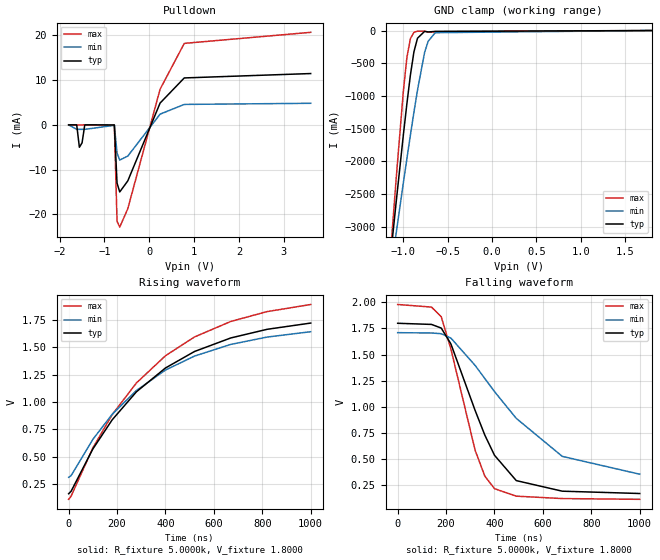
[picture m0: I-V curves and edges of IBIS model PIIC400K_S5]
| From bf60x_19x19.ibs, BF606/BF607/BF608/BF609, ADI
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[Model]  PIIC400K_S5
Model_type I/O_open_drain
Polarity   Non-Inverting
Enable   Active-Low
Vinl =   0.5400V
Vinh =   1.2600V
Vmeas =  0.9000V
Cref =   50.0000pF
Rref =   5.0000k
Vref =   1.8000V
C_comp   5.3246pF   5.6155pF   5.1879pF
[Temperature Range]   25.0000   0.1250k   -40.0000
[Voltage Range]   1.8000V   1.7100V   1.9800V
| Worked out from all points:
|   slope of the pulldown table from 0 to 0.27 V, typ, clamps not added: 50.4 ohm
|   rising waveform, R_fixture 5.0000k, V_fixture 1.8000: 20-80 % time 397ns typ, 397ns min, 398ns max; typ from 0.161 V to 1.72 V
|   falling waveform, R_fixture 5.0000k, V_fixture 1.8000: 20-80 % time 168ns typ, 306ns min, 119ns max; typ from 1.8 V to 0.168 V
[Pulldown]
|Voltage   I(typ)   I(min)   I(max)
-1.8V     0A         0A         0A
-1.62V    0A         -1mA       0A
-1.56V    -5mA       -1mA       0A
-1.5V     -4mA       -1mA       0A
-1.44V    0A         -1mA       0A
-780mV    -20uA      -100uA     -63uA
-720mV    -13.01mA   -6.3mA     -21.52mA
-660mV    -14.98mA   -7.86mA    -22.85mA
-480mV    -12.51mA   -6.972mA   -18.72mA
240mV     4.868mA    2.395mA    7.96mA
780mV     10.49mA    4.573mA    18.21mA
3.6V      11.47mA    4.825mA    20.68mA
[GND_clamp]
|Voltage   I(typ)   I(min)   I(max)
-1.8V     -12.65A    -10.37A    -16.09A
-1.12V    -3.145A    -3.485A    -2.97A
-1.08V    -2.62A     -3.098A    -2.26A
-1V       -1.604A    -2.336A    -936.9mA
-960mV    -1.124A    -1.964A    -416mA
-920mV    -680.1mA   -1.6A      -122.9mA
-880mV    -323.6mA   -1.247A    -27.4mA
-840mV    -117.5mA   -911.1mA   -9.271mA
-760mV    -12.74mA   -333.5mA   -9.089mA
-720mV    -21.78mA   -164.5mA   -26.29mA
-640mV    -13.84mA   -32.86mA   -16.42mA
1.8V      194.7pA    170.9uA    -341.8uA
[Ramp]
| variable   typ   min   max
dV/dt_r  0.9370/0.3980u   0.7991/0.3975u   1.0696/0.3987u
dV/dt_f  0.9790/0.1682u   0.8140/0.3064u   1.1205/0.1189u
R_load = 5.0000k
[Rising Waveform]
R_fixture= 5.0000k
V_fixture= 1.8000
V_fixture_min= 1.7100
V_fixture_max= 1.9800
|time   V(typ)   V(min)   V(max)
0s        161.3mV    312.2mV    110.3mV
10.1ns    183.6mV    327.1mV    138.9mV
100ns     570.9mV    658.8mV    580.4mV
180ns     838mV      888.6mV    885.3mV
280ns     1.094V     1.106V     1.175V
400ns     1.312V     1.293V     1.424V
520ns     1.463V     1.421V     1.596V
670ns     1.587V     1.528V     1.738V
820ns     1.666V     1.595V     1.828V
1us       1.723V     1.644V     1.893V
[Falling Waveform]
R_fixture= 5.0000k
V_fixture= 1.8000
V_fixture_min= 1.7100
V_fixture_max= 1.9800
|time   V(typ)   V(min)   V(max)
0s        1.8V       1.71V      1.98V
140ns     1.789V     1.707V     1.955V
180ns     1.754V     1.7V       1.863V
220ns     1.602V     1.658V     1.553V
320ns     964.5mV    1.396V     582.7mV
360ns     728.8mV    1.271V     335.7mV
400ns     535mV      1.145V     214.7mV
490ns     292mV      888.6mV    142.9mV
680ns     190.6mV    524.3mV    119.8mV
1us       168.3mV    353.3mV    112.5mV
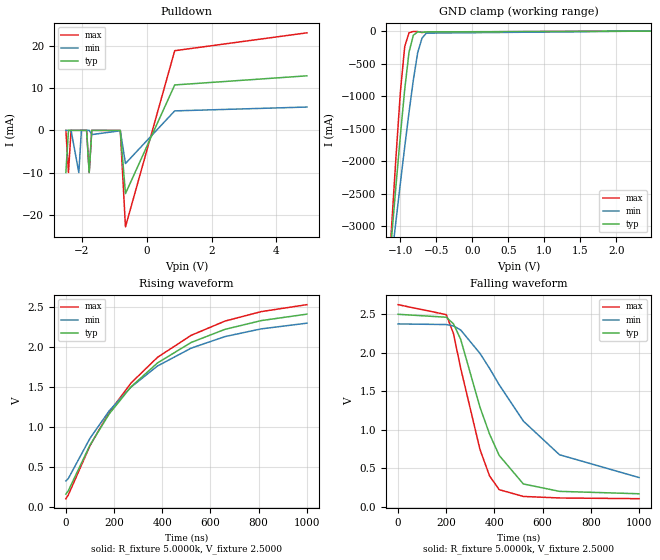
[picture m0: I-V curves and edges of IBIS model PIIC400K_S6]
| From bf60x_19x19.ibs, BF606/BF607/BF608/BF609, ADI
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[Model]  PIIC400K_S6
Model_type I/O_open_drain
Polarity   Non-Inverting
Enable   Active-Low
Vinl =   0.7500V
Vinh =   1.7500V
Vmeas =  1.2500V
Cref =   50.0000pF
Rref =   5.0000k
Vref =   2.5000V
C_comp   5.3246pF   5.6155pF   5.1879pF
[Temperature Range]   25.0000   0.1250k   -40.0000
[Voltage Range]   2.5000V   2.3750V   2.6250V
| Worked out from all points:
|   slope of the pulldown table from 0 to 0.375 V, typ, clamps not added: 53.9 ohm
|   rising waveform, R_fixture 5.0000k, V_fixture 2.5000: 20-80 % time 388ns typ, 387ns min, 388ns max; typ from 0.162 V to 2.4 V
|   falling waveform, R_fixture 5.0000k, V_fixture 2.5000: 20-80 % time 151ns typ, 283ns min, 114ns max; typ from 2.5 V to 0.17 V
[Pulldown]
|Voltage   I(typ)   I(min)   I(max)
-2.5V     -10mA      0A         0A
-2.42V    0A         0A         -10mA
-2.34V    0A         0A         0A
-2.1V     0A         -10mA      0A
-2.02V    0A         0A         0A
-1.86V    0A         0A         0A
-1.78V    -10mA      0A         -10mA
-1.7V     0A         -1mA       0A
-820mV    -10uA      -100uA     -40uA
-660mV    -14.98mA   -7.85mA    -22.85mA
860mV     10.75mA    4.61mA     18.86mA
4.94V     12.91mA    5.518mA    23.09mA
[GND_clamp]
|Voltage   I(typ)   I(min)   I(max)
-2.5V     -22.63A    -17.59A    -29.91A
-1.18V    -3.946A    -4.071A    -4.065A
-1.12V    -3.144A    -3.484A    -2.969A
-1.06V    -2.36A     -2.905A    -1.913A
-1V       -1.603A    -2.335A    -935.8mA
-940mV    -896mA     -1.78A     -238mA
-880mV    -322.8mA   -1.246A    -26.45mA
-820mV    -64.33mA   -750.1mA   -6.365mA
-760mV    -12.04mA   -332.8mA   -8.208mA
-700mV    -18.86mA   -109.3mA   -22.94mA
-640mV    -13.21mA   -32.25mA   -15.62mA
2.48V     -25.53uA   134uA      -185.1uA
[Ramp]
| variable   typ   min   max
dV/dt_r  1.3458/0.3887u   1.1797/0.3876u   1.4512/0.3889u
dV/dt_f  1.3977/0.1507u   1.1963/0.2827u   1.5110/0.1142u
R_load = 5.0000k
[Rising Waveform]
R_fixture= 5.0000k
V_fixture= 2.5000
V_fixture_min= 2.3750
V_fixture_max= 2.6250
|time   V(typ)   V(min)   V(max)
0s        162mV      325.8mV    104.3mV
10.1ns    202.9mV    355.2mV    150.7mV
100ns     772.2mV    856.6mV    764.1mV
180ns     1.162V     1.2V       1.183V
270ns     1.498V     1.495V     1.545V
380ns     1.796V     1.758V     1.866V
520ns     2.052V     1.981V     2.141V
660ns     2.215V     2.125V     2.318V
810ns     2.324V     2.221V     2.436V
1us       2.405V     2.292V     2.523V
[Falling Waveform]
R_fixture= 5.0000k
V_fixture= 2.5000
V_fixture_min= 2.3750
V_fixture_max= 2.6250
|time   V(typ)   V(min)   V(max)
0s        2.5V       2.375V     2.625V
200ns     2.462V     2.367V     2.496V
230ns     2.376V     2.349V     2.25V
260ns     2.175V     2.296V     1.799V
340ns     1.294V     1.993V     746.1mV
380ns     943.2mV    1.797V     400.8mV
420ns     667.2mV    1.584V     223.5mV
520ns     297.9mV    1.114V     135.9mV
670ns     201.8mV    677mV      115.9mV
1us       170.5mV    381.1mV    106.7mV
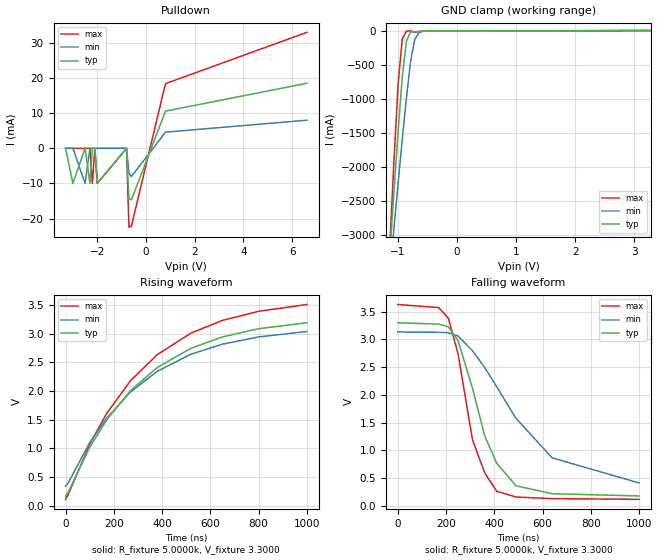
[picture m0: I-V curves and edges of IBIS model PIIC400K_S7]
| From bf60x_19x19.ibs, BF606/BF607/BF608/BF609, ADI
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[Model]  PIIC400K_S7
Model_type I/O_open_drain
Polarity   Non-Inverting
Enable   Active-Low
Vinl =   0.9900V
Vinh =   2.3100V
Vmeas =  1.6500V
Cref =   50.0000pF
Rref =   5.0000k
Vref =   3.3000V
C_comp   5.3246pF   5.6155pF   5.1879pF
[Temperature Range]   25.0000   0.1250k   -40.0000
[Voltage Range]   3.3000V   3.1350V   3.6300V
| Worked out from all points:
|   slope of the pulldown table from 0 to 0.495 V, typ, clamps not added: 58.9 ohm
|   rising waveform, R_fixture 5.0000k, V_fixture 3.3000: 20-80 % time 376ns typ, 375ns min, 375ns max; typ from 0.166 V to 3.19 V
|   falling waveform, R_fixture 5.0000k, V_fixture 3.3000: 20-80 % time 131ns typ, 266ns min, 97.1ns max; typ from 3.3 V to 0.175 V
[Pulldown]
|Voltage   I(typ)   I(min)   I(max)
-3.3V     0A         0A         0A
-3V       -10mA      0A         0A
-2.5V     0A         -10mA      0A
-2.3V     -10mA      0A         0A
-2.2V     0A         0A         -10mA
-2.1V     0A         0A         0A
-2V       -10mA      0A         -10mA
-800mV    -10uA      0A         -49uA
-700mV    -14.38mA   -7mA       -22.45mA
-600mV    -14.69mA   -8.06mA    -22.16mA
800mV     10.57mA    4.585mA    18.39mA
6.6V      18.5mA     7.993mA    33mA
[GND_clamp]
|Voltage   I(typ)   I(min)   I(max)
-3.3V     -34.1A     -25.87A    -45.77A
-1.13V    -3.276A    -3.581A    -3.149A
-1.06V    -2.359A    -2.904A    -1.912A
-990mV    -1.48A     -2.241A    -788.7mA
-920mV    -678.9mA   -1.599A    -121.6mA
-850mV    -153.9mA   -992.2mA   -10.04mA
-780mV    -19.02mA   -453.9mA   -5.201mA
-710mV    -19.61mA   -133.8mA   -23.98mA
-640mV    -12.86mA   -31.91mA   -15.41mA
-570mV    -7.986mA   -10.87mA   -8.797mA
3.28V     -18.57uA   134.8uA    -325.1uA
[Ramp]
| variable   typ   min   max
dV/dt_r  1.8147/0.3763u   1.6160/0.3756u   2.0384/0.3760u
dV/dt_f  1.8748/0.1306u   1.6349/0.2664u   2.1094/97.1312n
R_load = 5.0000k
[Rising Waveform]
R_fixture= 5.0000k
V_fixture= 3.3000
V_fixture_min= 3.1350
V_fixture_max= 3.6300
|time   V(typ)   V(min)   V(max)
0s        166.5mV    344.7mV    111.7mV
10.1ns    229.6mV    392.6mV    187.8mV
100ns     1.019V     1.1V       1.073V
170ns     1.496V     1.526V     1.607V
270ns     2.011V     1.987V     2.184V
380ns     2.411V     2.344V     2.634V
520ns     2.747V     2.643V     3.011V
650ns     2.944V     2.817V     3.232V
800ns     3.086V     2.944V     3.391V
1us       3.191V     3.038V     3.509V
[Falling Waveform]
R_fixture= 5.0000k
V_fixture= 3.3000
V_fixture_min= 3.1350
V_fixture_max= 3.6300
|time   V(typ)   V(min)   V(max)
0s        3.3V       3.135V     3.63V
170ns     3.277V     3.128V     3.574V
210ns     3.227V     3.121V     3.38V
250ns     2.977V     3.062V     2.739V
310ns     2.117V     2.795V     1.188V
360ns     1.266V     2.496V     594.8mV
410ns     766.9mV    2.146V     261.3mV
490ns     358.9mV    1.576V     156.1mV
640ns     215.7mV    863mV      127mV
1us       175.4mV    410.2mV    114.4mV
